VERSION 5.7 ;
DIVIDERCHAR "/" ;
BUSBITCHARS "[]" ;

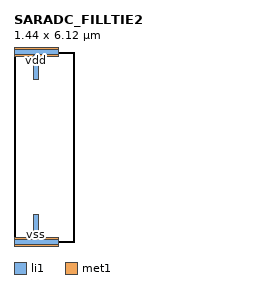
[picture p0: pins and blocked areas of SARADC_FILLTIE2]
MACRO SARADC_FILLTIE2
  CLASS BLOCK ;
  FOREIGN SARADC_FILLTIE2 ;
  ORIGIN 0.000 0.000 ;
  SIZE 1.440 BY 6.120 ;
  SYMMETRY X Y R90 ;
  PIN vdd
    DIRECTION INOUT ;
    USE POWER ;
    PORT
      LAYER li1 ;
        RECT 0.635 5.235 0.805 6.035 ;
        RECT 0.000 6.035 1.440 6.205 ;
      LAYER met1 ;
        RECT 0.000 5.985 1.440 6.255 ;
    END
  END vdd
  PIN vss
    DIRECTION INOUT ;
    USE GROUND ;
    PORT
      LAYER li1 ;
        RECT 0.000 -0.085 1.440 0.085 ;
        RECT 0.635 0.085 0.805 0.885 ;
      LAYER met1 ;
        RECT 0.000 -0.135 1.440 0.135 ;
    END
  END vss
END SARADC_FILLTIE2

END LIBRARY
